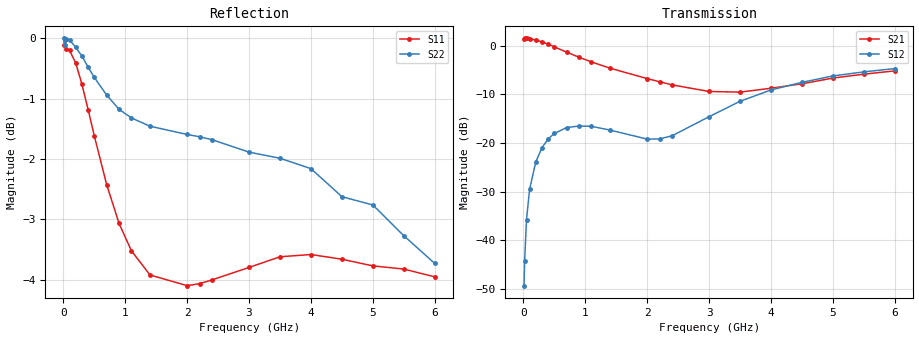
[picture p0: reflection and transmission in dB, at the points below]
! Infineon Technologies  Discrete & RF Semiconductors
! BFS17W
! Si NPN RF Bipolar Junction Transistor in SOT323
! VCE = 8 V  IC = 0.3 mA
! Common Emitter S-Parameters:  August  1999
# GHz  S  MA  R  50
!  f  S11  S21  S12  S22
! GHz  MAG  ANG  MAG  ANG  MAG  ANG  MAG  ANG
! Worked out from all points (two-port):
!   36 points, 10 MHz to 6 GHz, reference 50 ohm
!   highest |S21| = 1.54 dB at 20 MHz (marker M1); lowest = -9.5 dB at 3.5 GHz (marker M2)
!   |S21| within 3 dB of the highest: start of sweep to 730.2 MHz
!   lowest |S11| = -4.1 dB at 2 GHz (marker M3), VSWR 4.32, Z = 11.6 + j2.02 ohm
!   |S11| at or under -10 dB: nowhere
!   |S22| runs from -3.7 to 0.0 dB; largest |S21 - S12| = 1.2
!   S11 on the Smith chart (normalised r, x): 10 MHz: 31, -61; 300 MHz: 0.27, -2.27; 700 MHz: 0.24, -0.85; 1.4 GHz: 0.23, -0.23; 3 GHz: 0.25, +0.38; 6 GHz: 0.54, +1.11
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0.01  0.9868 -1.5  1.187 179.4  0.0034 83.2  0.9999 0.1
0.02  0.9966 -3.6  1.194 177.5  0.0061 91.0  0.9864 -0.8
0.05  0.9804 -8.1  1.192 173.2  0.0163 85.7  0.9978 -2.1
0.1  0.9772 -15.9  1.177 166.8  0.0334 80.5  0.9971 -4.1
0.2  0.9539 -31.9  1.15 153.1  0.0639 71.2  0.9827 -8.0
0.3  0.9161 -47.0  1.097 140.7  0.0894 62.0  0.9668 -11.5
0.4  0.873 -61.1  1.04 128.9  0.1103 54.0  0.9464 -14.8
0.5  0.8302 -73.9  0.975 118.5  0.1253 47.4  0.9281 -17.6
0.7  0.7565 -97.0  0.861 100.5  0.1443 37.0  0.8974 -22.8
0.9  0.7026 -116.1  0.763 86.0  0.1496 29.2  0.8734 -27.6
1.1  0.6668 -132.5  0.683 73.9  0.1484 24.3  0.8591 -32.3
1.4  0.6369 -153.2  0.589 59.9  0.1359 21.2  0.8457 -39.5
2  0.624 175.1  0.46 41.6  0.1096 35.0  0.8325 -55.2
2.2  0.6264 166.5  0.427 37.9  0.1102 45.1  0.8289 -60.7
2.4  0.6309 158.5  0.397 35.5  0.1185 55.4  0.8243 -66.4
3  0.6461 136.6  0.339 35.3  0.1866 71.7  0.8049 -83.2
3.5  0.6594 121.5  0.334 39.9  0.2686 71.4  0.7956 -97.9
4  0.6622 108.8  0.366 43.3  0.3519 65.5  0.78 -113.9
4.5  0.6563 97.8  0.407 43.0  0.4212 57.9  0.7394 -129.1
5  0.648 89.4  0.466 40.2  0.49 50.4  0.7278 -142.9
5.5  0.6441 82.3  0.511 36.0  0.5396 42.8  0.6864 -157.1
6  0.6346 76.8  0.553 31.1  0.5837 36.0  0.651 -169.5
